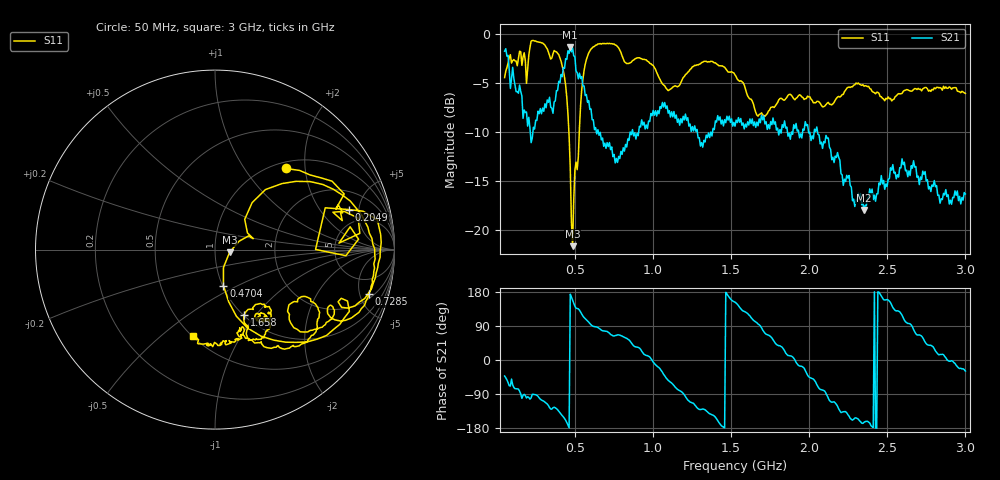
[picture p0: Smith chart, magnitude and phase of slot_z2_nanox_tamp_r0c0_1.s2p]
! nanovna_capture.py 2026-10-26T21:32:38+0900
! NanoVNA-F_V2 fw 0.6.0 SN 4A3639384505514B
! cal: load open short thru cal'ed  over 50000000-3000000000 Hz, 201 points
! points 401, avg 4
! slot line z=1.6, tampered Nano X, 0 deg (length across slot, USB toward SIG), centred, placement 1
# HZ S RI R 50
! S12 and S22 are not measured (written as 0)
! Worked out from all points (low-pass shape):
!   401 points, 50 MHz to 3 GHz, reference 50 ohm
!   highest |S21| = -1.32 dB at 470.4 MHz (marker M1); lowest = -18.0 dB at 2.351 GHz (marker M2)
!   |S21| within 3 dB of the highest: start of sweep to 82.11 MHz; 419 MHz to 519 MHz (100 MHz wide, 21.3 % of centre) (the widest 2 of 5)
!   lowest |S11| = -21.7 dB at 485.1 MHz (marker M3), VSWR 1.18, Z = 58.8 - j1.77 ohm
!   |S11| at or under -10 dB: 461.6 MHz to 528.2 MHz (66.64 MHz wide, 13.5 % of centre)
!   S12 and S22 are empty: the file has one direction only
!   S11 on the Smith chart (normalised r, x): 50 MHz: 1.12, +1.58; 204.9 MHz: 3.45, +3.90; 470.4 MHz: 1.01, -0.43; 728.5 MHz: 2.53, -6.10; 1.658 GHz: 1.01, -0.87; 3 GHz: 0.50, -0.64
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5e7  0.3936 0.4519  0.6048 -0.5501  0 0  0 0
1.75375e8  0.7997 0.0579  -0.00391 -0.4094  0 0  0 0
2.04875e8  0.746 0.223  -0.0582 -0.3715  0 0  0 0
2.63875e8  0.9061 -0.1026  -0.0416 -0.4016  0 0  0 0
4.04e8  0.5681 -0.4993  -0.4274 -0.3687  0 0  0 0
4.4825e8  0.181 -0.437  -0.7166 -0.1925  0 0  0 0
4.70375e8  0.0472 -0.2017  -0.8534 0.0953  0 0  0 0
4.85125e8  0.0813 -0.0149  -0.7891 0.3156  0 0  0 0
5.44125e8  0.373 0.3678  -0.31 0.5209  0 0  0 0
6.105e8  0.8331 0.1605  -0.00169 0.3652  0 0  0 0
7.285e8  0.8578 -0.2459  0.0985 0.2375  0 0  0 0
1.03825e9  0.4286 -0.419  0.3684 -0.1345  0 0  0 0
1.207875e9  0.5476 -0.293  -0.045 -0.3876  0 0  0 0
1.525e9  0.2896 -0.5464  -0.3005 0.1558  0 0  0 0
1.65775e9  0.161 -0.3646  -0.0602 0.3287  0 0  0 0
1.842125e9  0.2994 -0.3486  0.3279 0.149  0 0  0 0
2.019125e9  0.2326 -0.395  0.1987 -0.2278  0 0  0 0
2.18875e9  0.2845 -0.3871  -0.1477 -0.1823  0 0  0 0
2.351e9  0.2123 -0.4983  -0.1217 -0.0341  0 0  0 0
2.51325e9  0.1462 -0.444  -0.1662 0.0763  0 0  0 0
2.668125e9  0.1158 -0.5076  0.0367 0.2226  0 0  0 0
3e9  -0.1233 -0.4818  0.1333 -0.0743  0 0  0 0
